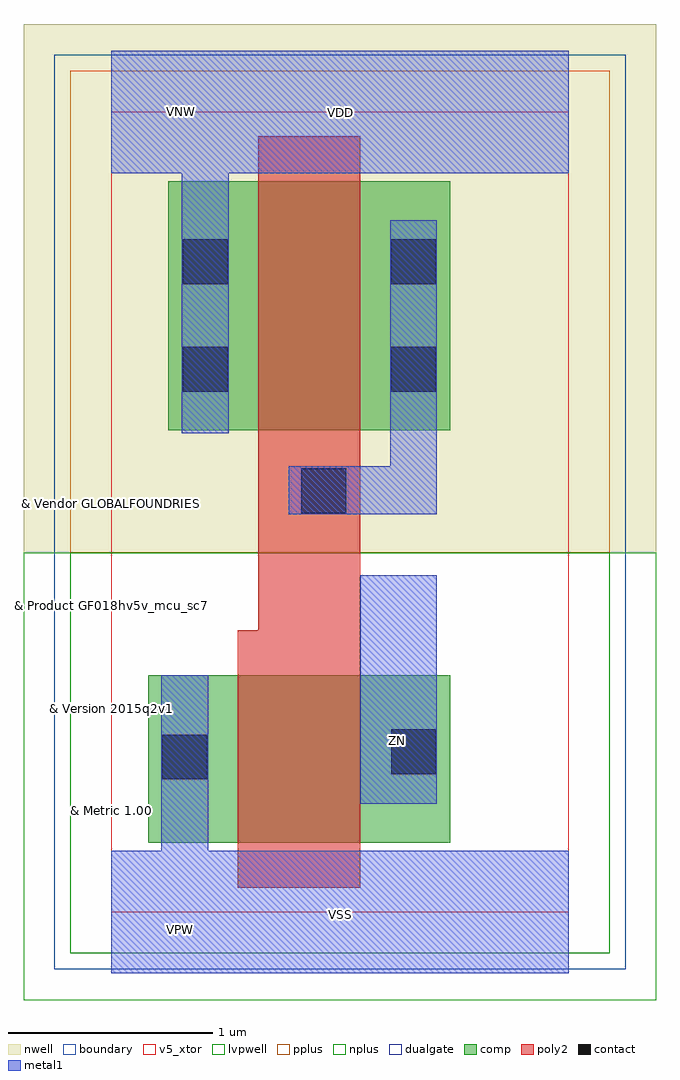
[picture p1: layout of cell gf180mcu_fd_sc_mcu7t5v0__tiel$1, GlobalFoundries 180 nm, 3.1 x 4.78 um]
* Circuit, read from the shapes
.subckt gf180mcu_fd_sc_mcu7t5v0__tiel$1 VDD VNW VSS ZN
XM1 ZN n1 VSS VSUBS nfet_05v0 w=0.82u l=0.6u
XM2 n1 n1 VDD VNW pfet_05v0 w=1.22u l=0.5u
.ends

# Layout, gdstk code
import gdstk
lib = gdstk.Library(unit=1e-6, precision=1e-09)
def R(c, l, rs):  # rectangles x0, y0, x1, y1
    for r in rs: c.add(gdstk.rectangle(r[:2], r[2:], *l))
def P(c, l, *ps):  # polygons
    for p in ps: c.add(gdstk.Polygon(p, *l))
boundary = (0, 0)
nwell = (21, 0)
comp = (22, 0)
poly2 = (30, 0)
pplus = (31, 0)
nplus = (32, 0)
contact = (33, 0)
metal1 = (34, 0)
dualgate = (55, 0)
v5_xtor = (112, 1)
lvpwell = (204, 0)

gf180mcu_fd_sc_mcu7t5v0_ = lib.new_cell('gf180mcu_fd_sc_mcu7t5v0__tiel$1')
R(gf180mcu_fd_sc_mcu7t5v0_, boundary, [(0,0,2.24,3.92)])
R(gf180mcu_fd_sc_mcu7t5v0_, nwell, [(-0.43,1.76,2.67,4.35)])
R(gf180mcu_fd_sc_mcu7t5v0_, comp, [(0.18,0.34,1.66,1.16), (0.28,2.36,1.66,3.58)])
P(gf180mcu_fd_sc_mcu7t5v0_, poly2, [(0.62,0.12),(0.62,1.38),(0.72,1.38),(0.72,3.8),(1.22,3.8),(1.22,0.12)])
R(gf180mcu_fd_sc_mcu7t5v0_, pplus, [(-0.2,1.76,2.44,4.12)])
R(gf180mcu_fd_sc_mcu7t5v0_, nplus, [(-0.2,-0.2,2.44,1.76)])
R(gf180mcu_fd_sc_mcu7t5v0_, contact, [(0.25,0.65,0.47,0.87), (1.37,0.675,1.59,0.895), (0.93,1.955,1.15,2.175), (0.35,2.55,0.57,2.77), (1.37,2.55,1.59,2.77), (0.35,3.075,0.57,3.295), (1.37,3.075,1.59,3.295)])
R(gf180mcu_fd_sc_mcu7t5v0_, metal1, [(1.22,0.53,1.595,1.65)])
P(gf180mcu_fd_sc_mcu7t5v0_, metal1, [(0.87,1.95),(0.87,2.185),(1.365,2.185),(1.365,3.39),(1.595,3.39),(1.595,1.95)],
  [(0,-0.3),(0,0.3),(0.245,0.3),(0.245,1.16),(0.475,1.16),(0.475,0.3),(2.24,0.3),(2.24,-0.3)],
  [(0.345,2.345),(0.345,3.62),(0,3.62),(0,4.22),(2.24,4.22),(2.24,3.62),(0.575,3.62),(0.575,2.345)])
R(gf180mcu_fd_sc_mcu7t5v0_, dualgate, [(-0.28,-0.28,2.52,4.2)])
R(gf180mcu_fd_sc_mcu7t5v0_, v5_xtor, [(0,0,2.24,3.92)])
R(gf180mcu_fd_sc_mcu7t5v0_, lvpwell, [(-0.43,-0.43,2.67,1.76)])
gf180mcu_fd_sc_mcu7t5v0_.add(gdstk.Label('ZN', (1.4,0.84), layer=34, texttype=10))
gf180mcu_fd_sc_mcu7t5v0_.add(gdstk.Label('VDD', (1.12,3.915), layer=34, texttype=10))
gf180mcu_fd_sc_mcu7t5v0_.add(gdstk.Label('VSS', (1.12,-0.01), layer=34, texttype=10))
gf180mcu_fd_sc_mcu7t5v0_.add(gdstk.Label('& Vendor GLOBALFOUNDRIES', (0,2), layer=63, texttype=63))
gf180mcu_fd_sc_mcu7t5v0_.add(gdstk.Label('& Product GF018hv5v_mcu_sc7', (0,1.5), layer=63, texttype=63))
gf180mcu_fd_sc_mcu7t5v0_.add(gdstk.Label('& Version 2015q2v1', (0,1), layer=63, texttype=63))
gf180mcu_fd_sc_mcu7t5v0_.add(gdstk.Label('& Metric 1.00', (0,0.5), layer=63, texttype=63))
gf180mcu_fd_sc_mcu7t5v0_.add(gdstk.Label('VNW', (0.345,3.92), layer=21, texttype=10))
gf180mcu_fd_sc_mcu7t5v0_.add(gdstk.Label('VPW', (0.34,-0.085), layer=204, texttype=10))

lib.write_gds('gf180mcu_fd_sc_mcu7t5v0__tiel_1.gds')
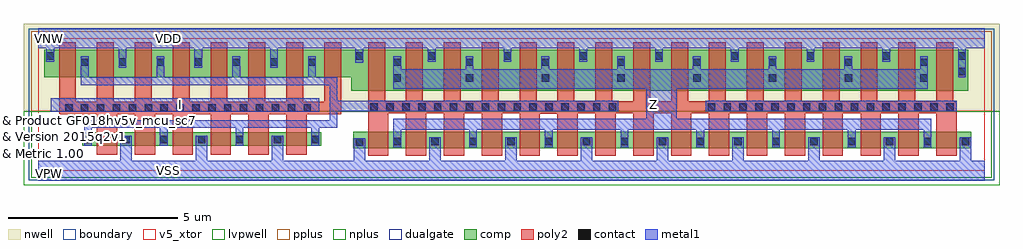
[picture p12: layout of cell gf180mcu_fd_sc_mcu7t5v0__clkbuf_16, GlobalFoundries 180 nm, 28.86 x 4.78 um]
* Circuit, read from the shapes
.subckt gf180mcu_fd_sc_mcu7t5v0__clkbuf_16 I VDD VNW VSS Z
XM1 VSS I n1 VSUBS nfet_05v0 w=0.405u l=0.6u m=6
XM2 Z n1 VSS VSUBS nfet_05v0 w=0.485u l=0.6u m=16
XM3 n1 I VDD VNW pfet_05v0 w=0.82u l=0.5u m=8
XM4 Z n1 VDD VNW pfet_05v0 w=1.22u l=0.5u m=16
.ends

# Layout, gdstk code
import gdstk
lib = gdstk.Library(unit=1e-6, precision=1e-09)
def R(c, l, rs):  # rectangles x0, y0, x1, y1
    for r in rs: c.add(gdstk.rectangle(r[:2], r[2:], *l))
def A(c, l, x, y, w, h, nx, ny, dx, dy):  # array of equal rectangles
    R(c, l, [(x+i*dx, y+j*dy, x+i*dx+w, y+j*dy+h) for i in range(nx) for j in range(ny)])
def P(c, l, *ps):  # polygons
    for p in ps: c.add(gdstk.Polygon(p, *l))
boundary = (0, 0)
nwell = (21, 0)
comp = (22, 0)
poly2 = (30, 0)
pplus = (31, 0)
nplus = (32, 0)
contact = (33, 0)
metal1 = (34, 0)
dualgate = (55, 0)
v5_xtor = (112, 1)
lvpwell = (204, 0)

gf180mcu_fd_sc_mcu7t5v0_ = lib.new_cell('gf180mcu_fd_sc_mcu7t5v0__clkbuf_16')
R(gf180mcu_fd_sc_mcu7t5v0_, boundary, [(0,0,28,3.92)])
R(gf180mcu_fd_sc_mcu7t5v0_, nwell, [(-0.43,1.76,28.43,4.35)])
R(gf180mcu_fd_sc_mcu7t5v0_, comp, [(9.32,0.665,27.6,1.15), (1.3,0.74,8.38,1.145)])
P(gf180mcu_fd_sc_mcu7t5v0_, comp, [(9.26,2.36),(9.26,2.76),(0.18,2.76),(0.18,3.58),(27.5,3.58),(27.5,2.36)])
P(gf180mcu_fd_sc_mcu7t5v0_, poly2, [(1.74,0.47),(1.74,1.675),(0.62,1.675),(0.62,3.8),(1.12,3.8),(1.12,2.035),(1.74,2.035),(1.74,3.8),(2.24,3.8),(2.24,2.035),(2.86,2.035),(2.86,3.8),(3.36,3.8),(3.36,2.035),(3.98,2.035),(3.98,3.8),(4.48,3.8),(4.48,2.035),(5.1,2.035),(5.1,3.8),(5.6,3.8),(5.6,2.035),(6.22,2.035),(6.22,3.8),(6.72,3.8),(6.72,2.035),(7.34,2.035),(7.34,3.8),(7.84,3.8),(7.84,2.035),(8.46,2.035),(8.46,3.8),(8.96,3.8),(8.96,1.675),(7.94,1.675),(7.94,0.47),(7.34,0.47),(7.34,1.675),(6.82,1.675),(6.82,0.47),(6.22,0.47),(6.22,1.675),(5.7,1.675),(5.7,0.47),(5.1,0.47),(5.1,1.675),(4.58,1.675),(4.58,0.47),(3.98,0.47),(3.98,1.675),(3.46,1.675),(3.46,0.47),(2.86,0.47),(2.86,1.675),(2.34,1.675),(2.34,0.47)],
  [(9.76,0.445),(9.76,3.8),(10.26,3.8),(10.26,2.06),(10.88,2.06),(10.88,3.8),(11.38,3.8),(11.38,2.06),(12,2.06),(12,3.8),(12.5,3.8),(12.5,2.06),(13.12,2.06),(13.12,3.8),(13.62,3.8),(13.62,2.06),(14.24,2.06),(14.24,3.8),(14.74,3.8),(14.74,2.06),(15.36,2.06),(15.36,3.8),(15.86,3.8),(15.86,2.06),(16.48,2.06),(16.48,3.8),(16.98,3.8),(16.98,2.06),(17.6,2.06),(17.6,3.8),(18.1,3.8),(18.1,2.06),(18.72,2.06),(18.72,3.8),(19.22,3.8),(19.22,2.06),(19.84,2.06),(19.84,3.8),(20.34,3.8),(20.34,2.06),(20.96,2.06),(20.96,3.8),(21.46,3.8),(21.46,2.06),(22.08,2.06),(22.08,3.8),(22.58,3.8),(22.58,2.06),(23.2,2.06),(23.2,3.8),(23.7,3.8),(23.7,2.06),(24.32,2.06),(24.32,3.8),(24.82,3.8),(24.82,2.06),(25.44,2.06),(25.44,3.8),(25.94,3.8),(25.94,2.06),(26.56,2.06),(26.56,3.8),(27.06,3.8),(27.06,2.06),(27.16,2.06),(27.16,0.445),(26.56,0.445),(26.56,1.7),(26.04,1.7),(26.04,0.445),(25.44,0.445),(25.44,1.7),(24.92,1.7),(24.92,0.445),(24.32,0.445),(24.32,1.7),(23.8,1.7),(23.8,0.445),(23.2,0.445),(23.2,1.7),(22.68,1.7),(22.68,0.445),(22.08,0.445),(22.08,1.7),(21.56,1.7),(21.56,0.445),(20.96,0.445),(20.96,1.7),(20.44,1.7),(20.44,0.445),(19.84,0.445),(19.84,1.7),(19.32,1.7),(19.32,0.445),(18.72,0.445),(18.72,1.7),(18.2,1.7),(18.2,0.445),(17.6,0.445),(17.6,1.7),(17.08,1.7),(17.08,0.445),(16.48,0.445),(16.48,1.7),(15.96,1.7),(15.96,0.445),(15.36,0.445),(15.36,1.69),(14.84,1.69),(14.84,0.445),(14.24,0.445),(14.24,1.7),(13.72,1.7),(13.72,0.445),(13.12,0.445),(13.12,1.7),(12.6,1.7),(12.6,0.445),(12,0.445),(12,1.7),(11.48,1.7),(11.48,0.445),(10.88,0.445),(10.88,1.7),(10.36,1.7),(10.36,0.445)])
R(gf180mcu_fd_sc_mcu7t5v0_, pplus, [(-0.2,1.76,28.2,4.12)])
R(gf180mcu_fd_sc_mcu7t5v0_, nplus, [(-0.2,-0.2,28.2,1.76)])
A(gf180mcu_fd_sc_mcu7t5v0_, contact, 10.51, 0.76, 0.22, 0.22, 16, 1, 1.12, 0)
A(gf180mcu_fd_sc_mcu7t5v0_, contact, 1.37, 0.81, 0.22, 0.22, 7, 1, 1.12, 0)
A(gf180mcu_fd_sc_mcu7t5v0_, contact, 0.8, 1.745, 0.22, 0.22, 16, 1, 0.47, 0)
A(gf180mcu_fd_sc_mcu7t5v0_, contact, 9.83, 1.77, 0.22, 0.22, 16, 1, 0.47, 0)
A(gf180mcu_fd_sc_mcu7t5v0_, contact, 19.8, 1.77, 0.22, 0.22, 16, 1, 0.47, 0)
A(gf180mcu_fd_sc_mcu7t5v0_, contact, 12.65, 2.63, 0.22, 0.22, 7, 2, 2.24, 0.47)
A(gf180mcu_fd_sc_mcu7t5v0_, contact, 1.27, 3.1, 0.22, 0.22, 4, 1, 2.24, 0)
A(gf180mcu_fd_sc_mcu7t5v0_, contact, 2.39, 3.11, 0.22, 0.22, 3, 1, 2.24, 0)
A(gf180mcu_fd_sc_mcu7t5v0_, contact, 11.53, 3.29, 0.22, 0.22, 8, 1, 2.24, 0)
R(gf180mcu_fd_sc_mcu7t5v0_, contact, [(9.39,0.735,9.61,0.955), (10.51,2.63,10.73,2.85), (27.21,2.82,27.43,3.04), (10.51,3.1,10.73,3.32), (0.25,3.29,0.47,3.51), (9.39,3.29,9.61,3.51)])
R(gf180mcu_fd_sc_mcu7t5v0_, metal1, [(0.37,1.74,8.31,2.15), (19.74,1.765,27.16,2.065)])
P(gf180mcu_fd_sc_mcu7t5v0_, metal1, [(1.365,0.74),(1.365,1.5),(8.62,1.5),(8.62,2.53),(1.265,2.53),(1.265,3.39),(1.495,3.39),(1.495,2.76),(3.505,2.76),(3.505,3.39),(3.735,3.39),(3.735,2.76),(5.745,2.76),(5.745,3.39),(5.975,3.39),(5.975,2.76),(7.985,2.76),(7.985,3.39),(8.215,3.39),(8.215,2.76),(8.85,2.76),(8.85,2.065),(17.16,2.065),(17.16,1.765),(8.85,1.765),(8.85,1.27),(8.315,1.27),(8.315,0.74),(8.085,0.74),(8.085,1.27),(6.075,1.27),(6.075,0.74),(5.845,0.74),(5.845,1.27),(3.835,1.27),(3.835,0.74),(3.605,0.74),(3.605,1.27),(1.595,1.27),(1.595,0.74)],
  [(10.505,0.69),(10.505,1.535),(17.985,1.535),(17.985,2.42),(10.505,2.42),(10.505,3.39),(10.735,3.39),(10.735,3),(12.645,3),(12.645,3.39),(12.875,3.39),(12.875,3),(14.885,3),(14.885,3.39),(15.115,3.39),(15.115,3),(17.125,3),(17.125,3.39),(17.355,3.39),(17.355,3),(19.365,3),(19.365,3.39),(19.595,3.39),(19.595,3),(21.605,3),(21.605,3.39),(21.835,3.39),(21.835,3),(23.845,3),(23.845,3.39),(24.075,3.39),(24.075,3),(26.085,3),(26.085,3.39),(26.315,3.39),(26.315,2.42),(18.885,2.42),(18.885,1.535),(26.415,1.535),(26.415,0.69),(26.185,0.69),(26.185,1.215),(24.175,1.215),(24.175,0.69),(23.945,0.69),(23.945,1.215),(21.935,1.215),(21.935,0.69),(21.705,0.69),(21.705,1.215),(19.695,1.215),(19.695,0.69),(19.465,0.69),(19.465,1.215),(17.455,1.215),(17.455,0.69),(17.225,0.69),(17.225,1.215),(15.215,1.215),(15.215,0.69),(14.985,0.69),(14.985,1.215),(12.975,1.215),(12.975,0.69),(12.745,0.69),(12.745,1.215),(10.735,1.215),(10.735,0.69)],
  [(0,-0.3),(0,0.3),(2.43,0.3),(2.43,1.04),(2.77,1.04),(2.77,0.3),(4.67,0.3),(4.67,1.04),(5.01,1.04),(5.01,0.3),(6.91,0.3),(6.91,1.04),(7.25,1.04),(7.25,0.3),(9.33,0.3),(9.33,0.96),(9.67,0.96),(9.67,0.3),(11.57,0.3),(11.57,0.985),(11.91,0.985),(11.91,0.3),(13.81,0.3),(13.81,0.985),(14.15,0.985),(14.15,0.3),(16.05,0.3),(16.05,0.985),(16.39,0.985),(16.39,0.3),(18.29,0.3),(18.29,0.985),(18.63,0.985),(18.63,0.3),(20.53,0.3),(20.53,0.985),(20.87,0.985),(20.87,0.3),(22.77,0.3),(22.77,0.985),(23.11,0.985),(23.11,0.3),(25.01,0.3),(25.01,0.985),(25.35,0.985),(25.35,0.3),(27.25,0.3),(27.25,0.985),(27.59,0.985),(27.59,0.3),(28,0.3),(28,-0.3)],
  [(27.205,2.76),(27.205,3.62),(25.195,3.62),(25.195,3.23),(24.965,3.23),(24.965,3.62),(22.955,3.62),(22.955,3.23),(22.725,3.23),(22.725,3.62),(20.715,3.62),(20.715,3.23),(20.485,3.23),(20.485,3.62),(18.475,3.62),(18.475,3.23),(18.245,3.23),(18.245,3.62),(16.235,3.62),(16.235,3.23),(16.005,3.23),(16.005,3.62),(13.995,3.62),(13.995,3.23),(13.765,3.23),(13.765,3.62),(11.755,3.62),(11.755,3.23),(11.525,3.23),(11.525,3.62),(9.615,3.62),(9.615,3.19),(9.385,3.19),(9.385,3.62),(7.095,3.62),(7.095,3.05),(6.865,3.05),(6.865,3.62),(4.855,3.62),(4.855,3.05),(4.625,3.05),(4.625,3.62),(2.615,3.62),(2.615,3.05),(2.385,3.05),(2.385,3.62),(0.475,3.62),(0.475,3.23),(0.245,3.23),(0.245,3.62),(0,3.62),(0,4.22),(28,4.22),(28,3.62),(27.435,3.62),(27.435,2.76)])
R(gf180mcu_fd_sc_mcu7t5v0_, dualgate, [(-0.28,-0.28,28.28,4.2)])
R(gf180mcu_fd_sc_mcu7t5v0_, v5_xtor, [(0,0,28,3.92)])
R(gf180mcu_fd_sc_mcu7t5v0_, lvpwell, [(-0.43,-0.43,28.43,1.76)])
gf180mcu_fd_sc_mcu7t5v0_.add(gdstk.Label('VDD', (3.855,3.92), layer=34, texttype=10))
gf180mcu_fd_sc_mcu7t5v0_.add(gdstk.Label('VSS', (3.855,0), layer=34, texttype=10))
gf180mcu_fd_sc_mcu7t5v0_.add(gdstk.Label('Z', (18.2,1.96), layer=34, texttype=10))
gf180mcu_fd_sc_mcu7t5v0_.add(gdstk.Label('I', (4.2,1.96), layer=34, texttype=10))
gf180mcu_fd_sc_mcu7t5v0_.add(gdstk.Label('& Vendor GLOBALFOUNDRIES', (0,2), layer=63, texttype=63))
gf180mcu_fd_sc_mcu7t5v0_.add(gdstk.Label('& Product GF018hv5v_mcu_sc7', (0,1.5), layer=63, texttype=63))
gf180mcu_fd_sc_mcu7t5v0_.add(gdstk.Label('& Version 2015q2v1', (0,1), layer=63, texttype=63))
gf180mcu_fd_sc_mcu7t5v0_.add(gdstk.Label('& Metric 1.00', (0,0.5), layer=63, texttype=63))
gf180mcu_fd_sc_mcu7t5v0_.add(gdstk.Label('VNW', (0.345,3.92), layer=21, texttype=10))
gf180mcu_fd_sc_mcu7t5v0_.add(gdstk.Label('VPW', (0.34,-0.085), layer=204, texttype=10))

lib.write_gds('gf180mcu_fd_sc_mcu7t5v0__clkbuf_16.gds')
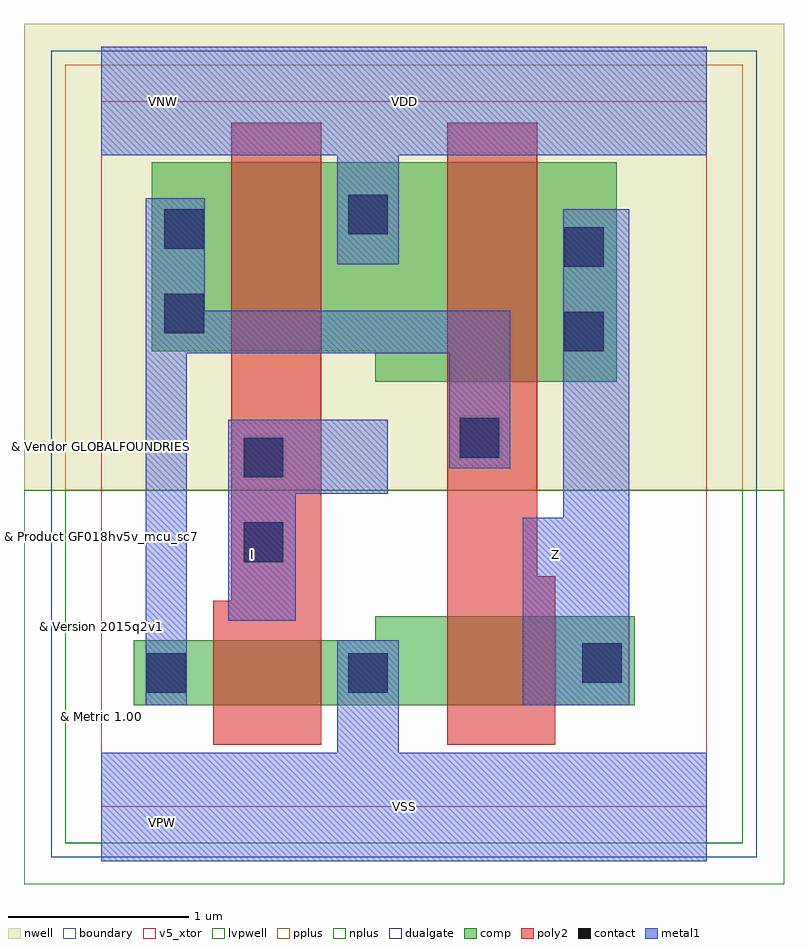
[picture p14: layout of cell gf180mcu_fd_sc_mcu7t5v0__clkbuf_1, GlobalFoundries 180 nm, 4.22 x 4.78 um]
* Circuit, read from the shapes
.subckt gf180mcu_fd_sc_mcu7t5v0__clkbuf_1 I VDD VNW VSS Z
XM1 VSS I n1 VSUBS nfet_05v0 w=0.36u l=0.6u
XM2 Z n1 VSS VSUBS nfet_05v0 w=0.495u l=0.6u
XM3 VDD I n1 VNW pfet_05v0 w=1.05u l=0.5u
XM4 Z n1 VDD VNW pfet_05v0 w=1.22u l=0.5u
.ends

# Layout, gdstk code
import gdstk
lib = gdstk.Library(unit=1e-6, precision=1e-09)
def R(c, l, rs):  # rectangles x0, y0, x1, y1
    for r in rs: c.add(gdstk.rectangle(r[:2], r[2:], *l))
def P(c, l, *ps):  # polygons
    for p in ps: c.add(gdstk.Polygon(p, *l))
boundary = (0, 0)
nwell = (21, 0)
comp = (22, 0)
poly2 = (30, 0)
pplus = (31, 0)
nplus = (32, 0)
contact = (33, 0)
metal1 = (34, 0)
dualgate = (55, 0)
v5_xtor = (112, 1)
lvpwell = (204, 0)

gf180mcu_fd_sc_mcu7t5v0_ = lib.new_cell('gf180mcu_fd_sc_mcu7t5v0__clkbuf_1')
R(gf180mcu_fd_sc_mcu7t5v0_, boundary, [(0,0,3.36,3.92)])
R(gf180mcu_fd_sc_mcu7t5v0_, nwell, [(-0.43,1.76,3.79,4.35)])
P(gf180mcu_fd_sc_mcu7t5v0_, comp, [(1.52,2.36),(1.52,2.53),(0.28,2.53),(0.28,3.58),(2.86,3.58),(2.86,2.36)],
  [(0.18,0.565),(0.18,0.925),(1.52,0.925),(1.52,1.06),(2.96,1.06),(2.96,0.565)])
P(gf180mcu_fd_sc_mcu7t5v0_, poly2, [(0.62,0.345),(0.62,1.145),(0.72,1.145),(0.72,3.8),(1.22,3.8),(1.22,0.345)],
  [(1.92,0.345),(1.92,3.8),(2.42,3.8),(2.42,1.28),(2.52,1.28),(2.52,0.345)])
R(gf180mcu_fd_sc_mcu7t5v0_, pplus, [(-0.2,1.76,3.56,4.12)])
R(gf180mcu_fd_sc_mcu7t5v0_, nplus, [(-0.2,-0.2,3.56,1.76)])
R(gf180mcu_fd_sc_mcu7t5v0_, contact, [(0.25,0.635,0.47,0.855), (1.37,0.635,1.59,0.855), (2.67,0.69,2.89,0.91), (0.79,1.36,1.01,1.58), (0.79,1.83,1.01,2.05), (1.99,1.94,2.21,2.16), (2.57,2.53,2.79,2.75), (0.35,2.63,0.57,2.85), (2.57,3,2.79,3.22), (0.35,3.1,0.57,3.32), (1.37,3.18,1.59,3.4)])
P(gf180mcu_fd_sc_mcu7t5v0_, metal1, [(0.705,1.035),(0.705,2.15),(1.59,2.15),(1.59,1.74),(1.08,1.74),(1.08,1.035)],
  [(0.245,0.565),(0.245,3.38),(0.575,3.38),(0.575,2.755),(2.27,2.755),(2.27,1.88),(1.93,1.88),(1.93,2.52),(0.475,2.52),(0.475,0.565)],
  [(2.34,0.565),(2.34,1.605),(2.565,1.605),(2.565,3.32),(2.93,3.32),(2.93,0.565)],
  [(0,-0.3),(0,0.3),(1.31,0.3),(1.31,0.925),(1.65,0.925),(1.65,0.3),(3.36,0.3),(3.36,-0.3)],
  [(1.31,3.015),(1.31,3.62),(0,3.62),(0,4.22),(3.36,4.22),(3.36,3.62),(1.65,3.62),(1.65,3.015)])
R(gf180mcu_fd_sc_mcu7t5v0_, dualgate, [(-0.28,-0.28,3.64,4.2)])
R(gf180mcu_fd_sc_mcu7t5v0_, v5_xtor, [(0,0,3.36,3.92)])
R(gf180mcu_fd_sc_mcu7t5v0_, lvpwell, [(-0.43,-0.43,3.79,1.76)])
gf180mcu_fd_sc_mcu7t5v0_.add(gdstk.Label('VSS', (1.68,0), layer=34, texttype=10))
gf180mcu_fd_sc_mcu7t5v0_.add(gdstk.Label('Z', (2.52,1.4), layer=34, texttype=10))
gf180mcu_fd_sc_mcu7t5v0_.add(gdstk.Label('I', (0.84,1.4), layer=34, texttype=10))
gf180mcu_fd_sc_mcu7t5v0_.add(gdstk.Label('VDD', (1.68,3.92), layer=34, texttype=10))
gf180mcu_fd_sc_mcu7t5v0_.add(gdstk.Label('& Vendor GLOBALFOUNDRIES', (0,2), layer=63, texttype=63))
gf180mcu_fd_sc_mcu7t5v0_.add(gdstk.Label('& Product GF018hv5v_mcu_sc7', (0,1.5), layer=63, texttype=63))
gf180mcu_fd_sc_mcu7t5v0_.add(gdstk.Label('& Version 2015q2v1', (0,1), layer=63, texttype=63))
gf180mcu_fd_sc_mcu7t5v0_.add(gdstk.Label('& Metric 1.00', (0,0.5), layer=63, texttype=63))
gf180mcu_fd_sc_mcu7t5v0_.add(gdstk.Label('VNW', (0.345,3.92), layer=21, texttype=10))
gf180mcu_fd_sc_mcu7t5v0_.add(gdstk.Label('VPW', (0.34,-0.085), layer=204, texttype=10))

lib.write_gds('gf180mcu_fd_sc_mcu7t5v0__clkbuf_1.gds')
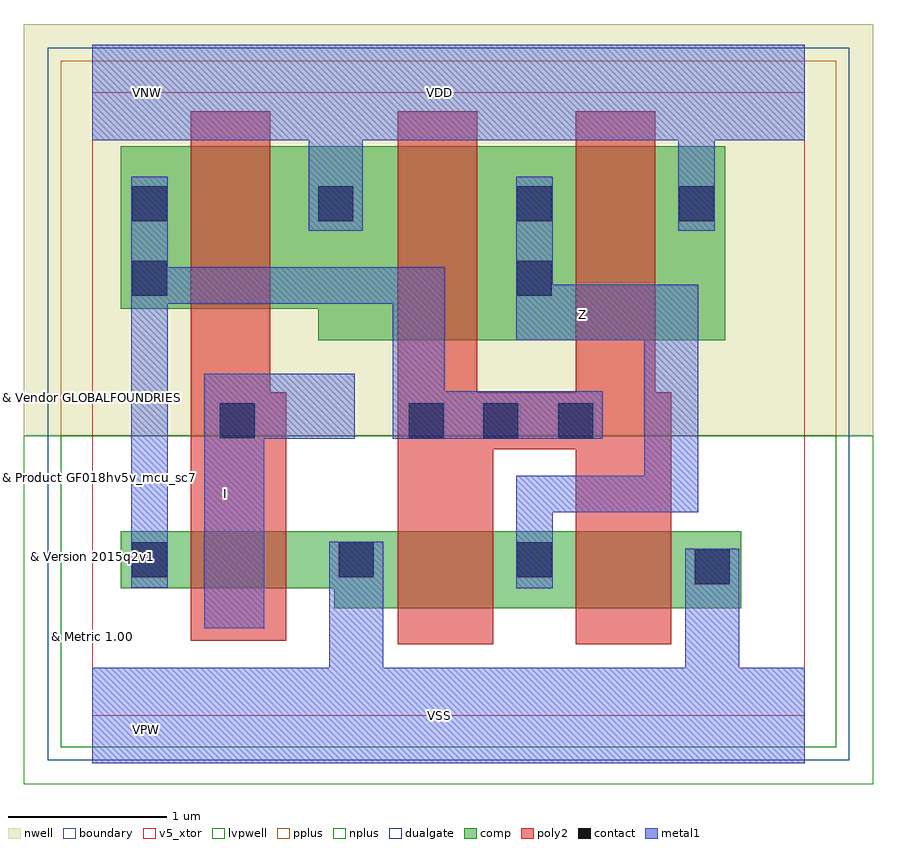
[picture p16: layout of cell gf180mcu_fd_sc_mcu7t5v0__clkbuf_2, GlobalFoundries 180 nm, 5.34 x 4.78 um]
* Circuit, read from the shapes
.subckt gf180mcu_fd_sc_mcu7t5v0__clkbuf_2 I VDD VNW VSS Z
XM1 VSS I n1 VSUBS nfet_05v0 w=0.36u l=0.6u
XM2 Z n1 VSS VSUBS nfet_05v0 w=0.485u l=0.6u m=2
XM3 VDD I n1 VNW pfet_05v0 w=1.02u l=0.5u
XM4 Z n1 VDD VNW pfet_05v0 w=1.22u l=0.5u m=2
.ends

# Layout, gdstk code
import gdstk
lib = gdstk.Library(unit=1e-6, precision=1e-09)
def R(c, l, rs):  # rectangles x0, y0, x1, y1
    for r in rs: c.add(gdstk.rectangle(r[:2], r[2:], *l))
def A(c, l, x, y, w, h, nx, ny, dx, dy):  # array of equal rectangles
    R(c, l, [(x+i*dx, y+j*dy, x+i*dx+w, y+j*dy+h) for i in range(nx) for j in range(ny)])
def P(c, l, *ps):  # polygons
    for p in ps: c.add(gdstk.Polygon(p, *l))
boundary = (0, 0)
nwell = (21, 0)
comp = (22, 0)
poly2 = (30, 0)
pplus = (31, 0)
nplus = (32, 0)
contact = (33, 0)
metal1 = (34, 0)
dualgate = (55, 0)
v5_xtor = (112, 1)
lvpwell = (204, 0)

gf180mcu_fd_sc_mcu7t5v0_ = lib.new_cell('gf180mcu_fd_sc_mcu7t5v0__clkbuf_2')
R(gf180mcu_fd_sc_mcu7t5v0_, boundary, [(0,0,4.48,3.92)])
R(gf180mcu_fd_sc_mcu7t5v0_, nwell, [(-0.43,1.76,4.91,4.35)])
P(gf180mcu_fd_sc_mcu7t5v0_, comp, [(1.42,2.36),(1.42,2.56),(0.18,2.56),(0.18,3.58),(3.98,3.58),(3.98,2.36)],
  [(1.52,0.675),(1.52,0.8),(0.18,0.8),(0.18,1.16),(4.08,1.16),(4.08,0.675)])
P(gf180mcu_fd_sc_mcu7t5v0_, poly2, [(0.62,0.47),(0.62,3.8),(1.12,3.8),(1.12,2.035),(1.22,2.035),(1.22,0.47)],
  [(1.92,0.45),(1.92,3.8),(2.42,3.8),(2.42,2.035),(3.04,2.035),(3.04,3.8),(3.54,3.8),(3.54,2.035),(3.64,2.035),(3.64,0.45),(3.04,0.45),(3.04,1.675),(2.52,1.675),(2.52,0.45)])
R(gf180mcu_fd_sc_mcu7t5v0_, pplus, [(-0.2,1.76,4.68,4.12)])
R(gf180mcu_fd_sc_mcu7t5v0_, nplus, [(-0.2,-0.2,4.68,1.76)])
A(gf180mcu_fd_sc_mcu7t5v0_, contact, 1.99, 1.745, 0.22, 0.22, 3, 1, 0.47, 0)
R(gf180mcu_fd_sc_mcu7t5v0_, contact, [(3.79,0.825,4.01,1.045), (0.25,0.87,0.47,1.09), (1.55,0.87,1.77,1.09), (2.67,0.87,2.89,1.09), (0.8,1.745,1.02,1.965), (0.25,2.64,0.47,2.86), (2.67,2.64,2.89,2.86), (0.25,3.11,0.47,3.33), (1.42,3.11,1.64,3.33), (2.67,3.11,2.89,3.33), (3.69,3.11,3.91,3.33)])
P(gf180mcu_fd_sc_mcu7t5v0_, metal1, [(0.705,0.55),(0.705,2.15),(1.65,2.15),(1.65,1.74),(1.08,1.74),(1.08,0.55)],
  [(0.245,0.805),(0.245,3.39),(0.475,3.39),(0.475,2.82),(2.215,2.82),(2.215,2.04),(3.21,2.04),(3.21,1.74),(1.89,1.74),(1.89,2.59),(0.475,2.59),(0.475,0.805)],
  [(2.665,0.8),(2.665,1.51),(3.47,1.51),(3.47,2.36),(2.665,2.36),(2.665,3.39),(2.895,3.39),(2.895,2.71),(3.81,2.71),(3.81,1.28),(2.895,1.28),(2.895,0.8)],
  [(0,-0.3),(0,0.3),(1.49,0.3),(1.49,1.095),(1.83,1.095),(1.83,0.3),(3.73,0.3),(3.73,1.05),(4.07,1.05),(4.07,0.3),(4.48,0.3),(4.48,-0.3)],
  [(1.36,3.05),(1.36,3.62),(0,3.62),(0,4.22),(4.48,4.22),(4.48,3.62),(3.915,3.62),(3.915,3.05),(3.685,3.05),(3.685,3.62),(1.7,3.62),(1.7,3.05)])
R(gf180mcu_fd_sc_mcu7t5v0_, dualgate, [(-0.28,-0.28,4.76,4.2)])
R(gf180mcu_fd_sc_mcu7t5v0_, v5_xtor, [(0,0,4.48,3.92)])
R(gf180mcu_fd_sc_mcu7t5v0_, lvpwell, [(-0.43,-0.43,4.91,1.76)])
gf180mcu_fd_sc_mcu7t5v0_.add(gdstk.Label('Z', (3.08,2.52), layer=34, texttype=10))
gf180mcu_fd_sc_mcu7t5v0_.add(gdstk.Label('VSS', (2.185,0), layer=34, texttype=10))
gf180mcu_fd_sc_mcu7t5v0_.add(gdstk.Label('VDD', (2.185,3.92), layer=34, texttype=10))
gf180mcu_fd_sc_mcu7t5v0_.add(gdstk.Label('I', (0.84,1.4), layer=34, texttype=10))
gf180mcu_fd_sc_mcu7t5v0_.add(gdstk.Label('& Vendor GLOBALFOUNDRIES', (0,2), layer=63, texttype=63))
gf180mcu_fd_sc_mcu7t5v0_.add(gdstk.Label('& Product GF018hv5v_mcu_sc7', (0,1.5), layer=63, texttype=63))
gf180mcu_fd_sc_mcu7t5v0_.add(gdstk.Label('& Version 2015q2v1', (0,1), layer=63, texttype=63))
gf180mcu_fd_sc_mcu7t5v0_.add(gdstk.Label('& Metric 1.00', (0,0.5), layer=63, texttype=63))
gf180mcu_fd_sc_mcu7t5v0_.add(gdstk.Label('VNW', (0.345,3.92), layer=21, texttype=10))
gf180mcu_fd_sc_mcu7t5v0_.add(gdstk.Label('VPW', (0.34,-0.085), layer=204, texttype=10))

lib.write_gds('gf180mcu_fd_sc_mcu7t5v0__clkbuf_2.gds')
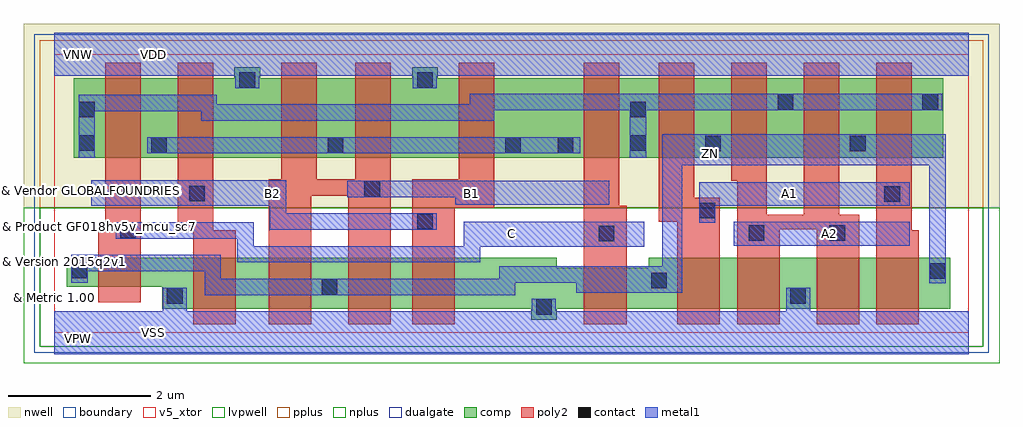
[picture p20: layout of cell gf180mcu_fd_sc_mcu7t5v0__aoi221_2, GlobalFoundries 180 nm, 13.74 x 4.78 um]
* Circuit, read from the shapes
.subckt gf180mcu_fd_sc_mcu7t5v0__aoi221_2 A1 A2 B1 B2 C VDD VNW VSS ZN
XM1 VSS C ZN VSUBS nfet_05v0 w=0.405u l=0.6u
XM2 n1 B2 VSS VSUBS nfet_05v0 w=0.715u l=0.6u
XM3 ZN B1 n1 VSUBS nfet_05v0 w=0.715u l=0.6u
XM4 n2 B1 ZN VSUBS nfet_05v0 w=0.715u l=0.6u
XM5 VSS B2 n2 VSUBS nfet_05v0 w=0.715u l=0.6u
XM6 ZN C VSS VSUBS nfet_05v0 w=0.575u l=0.6u
XM7 n3 A1 ZN VSUBS nfet_05v0 w=0.715u l=0.6u
XM8 VSS A2 n3 VSUBS nfet_05v0 w=0.715u l=0.6u
XM9 n4 A2 VSS VSUBS nfet_05v0 w=0.715u l=0.6u
XM10 ZN A1 n4 VSUBS nfet_05v0 w=0.715u l=0.6u
XM11 n5 C n6 VNW pfet_05v0 w=1.12u l=0.5u m=2
XM12 VDD B2 n5 VNW pfet_05v0 w=1.12u l=0.5u m=2
XM13 n5 B1 VDD VNW pfet_05v0 w=1.12u l=0.5u m=2
XM14 ZN A1 n6 VNW pfet_05v0 w=1.12u l=0.5u m=2
XM15 n6 A2 ZN VNW pfet_05v0 w=1.12u l=0.5u m=2
.ends

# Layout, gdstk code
import gdstk
lib = gdstk.Library(unit=1e-6, precision=1e-09)
def R(c, l, rs):  # rectangles x0, y0, x1, y1
    for r in rs: c.add(gdstk.rectangle(r[:2], r[2:], *l))
def P(c, l, *ps):  # polygons
    for p in ps: c.add(gdstk.Polygon(p, *l))
boundary = (0, 0)
nwell = (21, 0)
comp = (22, 0)
poly2 = (30, 0)
pplus = (31, 0)
nplus = (32, 0)
contact = (33, 0)
metal1 = (34, 0)
dualgate = (55, 0)
v5_xtor = (112, 1)
lvpwell = (204, 0)

gf180mcu_fd_sc_mcu7t5v0_ = lib.new_cell('gf180mcu_fd_sc_mcu7t5v0__aoi221_2')
R(gf180mcu_fd_sc_mcu7t5v0_, boundary, [(0,0,12.88,3.92)])
R(gf180mcu_fd_sc_mcu7t5v0_, nwell, [(-0.43,1.76,13.31,4.35)])
P(gf180mcu_fd_sc_mcu7t5v0_, comp, [(0.28,2.46),(0.28,3.58),(2.54,3.58),(2.54,3.74),(2.9,3.74),(2.9,3.58),(5.04,3.58),(5.04,3.74),(5.4,3.74),(5.4,3.58),(12.515,3.58),(12.515,2.46)],
  [(6.715,0.18),(6.715,0.34),(1.52,0.34),(1.52,0.65),(0.18,0.65),(0.18,1.055),(7.075,1.055),(7.075,0.915),(8.375,0.915),(8.375,1.055),(12.615,1.055),(12.615,0.34),(7.075,0.34),(7.075,0.18)])
P(gf180mcu_fd_sc_mcu7t5v0_, poly2, [(0.62,0.43),(0.62,1.44),(0.72,1.44),(0.72,3.8),(1.22,3.8),(1.22,0.43)],
  [(1.96,0.12),(1.96,1.46),(1.74,1.46),(1.74,3.8),(2.24,3.8),(2.24,1.44),(2.56,1.44),(2.56,0.12)],
  [(3.02,0.12),(3.02,2.16),(3.2,2.16),(3.2,3.8),(3.7,3.8),(3.7,2.16),(4.24,2.16),(4.24,3.8),(4.74,3.8),(4.74,0.12),(4.14,0.12),(4.14,1.93),(3.62,1.93),(3.62,0.12)],
  [(5.04,0.12),(5.04,2.16),(5.7,2.16),(5.7,3.8),(6.2,3.8),(6.2,1.76),(5.64,1.76),(5.64,0.12)],
  [(7.46,0.12),(7.46,3.8),(7.96,3.8),(7.96,1.79),(8.06,1.79),(8.06,0.12)],
  [(8.775,0.12),(8.775,1.56),(8.515,1.56),(8.515,3.8),(9.015,3.8),(9.015,1.9),(9.375,1.9),(9.375,0.12)],
  [(9.615,0.12),(9.615,2.14),(9.535,2.14),(9.535,3.8),(10.035,3.8),(10.035,1.66),(10.555,1.66),(10.555,3.8),(11.055,3.8),(11.055,1.66),(11.335,1.66),(11.335,0.12),(10.735,0.12),(10.735,1.46),(10.215,1.46),(10.215,0.12)],
  [(11.575,0.12),(11.575,3.8),(12.075,3.8),(12.075,1.44),(12.175,1.44),(12.175,0.12)])
R(gf180mcu_fd_sc_mcu7t5v0_, pplus, [(-0.2,1.76,13.08,4.12)])
R(gf180mcu_fd_sc_mcu7t5v0_, nplus, [(-0.2,-0.2,13.08,1.76)])
R(gf180mcu_fd_sc_mcu7t5v0_, contact, [(6.785,0.25,7.005,0.47), (1.59,0.41,1.81,0.63), (10.365,0.41,10.585,0.63), (3.77,0.535,3.99,0.755), (8.405,0.625,8.625,0.845), (12.325,0.76,12.545,0.98), (0.25,0.765,0.47,0.985), (7.665,1.285,7.885,1.505), (9.78,1.295,10,1.515), (10.915,1.295,11.135,1.515), (0.93,1.33,1.15,1.55), (5.11,1.455,5.33,1.675), (9.085,1.61,9.305,1.83), (11.69,1.845,11.91,2.065), (1.9,1.85,2.12,2.07), (4.37,1.915,4.59,2.135), (1.37,2.53,1.59,2.75), (3.85,2.53,4.07,2.75), (6.35,2.53,6.57,2.75), (7.09,2.53,7.31,2.75), (9.165,2.555,9.385,2.775), (11.205,2.555,11.425,2.775), (0.35,2.56,0.57,2.78), (8.11,2.56,8.33,2.78), (0.35,3.03,0.57,3.25), (8.11,3.03,8.33,3.25), (10.185,3.14,10.405,3.36), (12.225,3.14,12.445,3.36), (2.61,3.45,2.83,3.67), (5.11,3.45,5.33,3.67)])
R(gf180mcu_fd_sc_mcu7t5v0_, metal1, [(9.57,1.225,12.05,1.56), (1.31,2.525,7.41,2.755)])
P(gf180mcu_fd_sc_mcu7t5v0_, metal1, [(3.04,1.45),(3.04,1.785),(0.525,1.785),(0.525,2.15),(3.27,2.15),(3.27,1.68),(5.39,1.68),(5.39,1.45)],
  [(5.65,1.8),(5.65,1.91),(4.125,1.91),(4.125,2.14),(7.815,2.14),(7.815,1.8)],
  [(2.58,0.99),(2.58,1.325),(0.87,1.325),(0.87,1.555),(2.81,1.555),(2.81,1.22),(5.77,1.22),(5.77,1.56),(8.31,1.56),(8.31,1.21),(6,1.21),(6,0.99)],
  [(9.08,1.55),(9.08,2.12),(12.05,2.12),(12.05,1.79),(9.31,1.79),(9.31,1.55)],
  [(0.345,2.46),(0.345,3.35),(2.29,3.35),(2.29,3.215),(5.855,3.215),(5.855,3.365),(12.505,3.365),(12.505,3.135),(8.335,3.135),(8.335,2.46),(8.105,2.46),(8.105,3.135),(6.195,3.135),(6.195,2.985),(2.075,2.985),(2.075,3.12),(0.575,3.12),(0.575,2.46)],
  [(2.12,0.53),(2.12,0.865),(0.475,0.865),(0.475,0.705),(0.245,0.705),(0.245,1.095),(2.35,1.095),(2.35,0.76),(6.265,0.76),(6.265,0.935),(8.565,0.935),(8.565,2.795),(12.55,2.795),(12.55,0.7),(12.32,0.7),(12.32,2.36),(8.845,2.36),(8.845,0.565),(7.35,0.565),(7.35,0.705),(6.495,0.705),(6.495,0.53)],
  [(0,-0.3),(0,0.3),(1.53,0.3),(1.53,0.635),(1.87,0.635),(1.87,0.3),(6.725,0.3),(6.725,0.475),(7.065,0.475),(7.065,0.3),(10.305,0.3),(10.305,0.635),(10.645,0.635),(10.645,0.3),(12.88,0.3),(12.88,-0.3)],
  [(2.55,3.445),(2.55,3.62),(0,3.62),(0,4.22),(12.88,4.22),(12.88,3.62),(5.39,3.62),(5.39,3.445),(5.05,3.445),(5.05,3.62),(2.89,3.62),(2.89,3.445)])
R(gf180mcu_fd_sc_mcu7t5v0_, dualgate, [(-0.28,-0.28,13.16,4.2)])
R(gf180mcu_fd_sc_mcu7t5v0_, v5_xtor, [(0,0,12.88,3.92)])
R(gf180mcu_fd_sc_mcu7t5v0_, lvpwell, [(-0.43,-0.43,13.31,1.76)])
gf180mcu_fd_sc_mcu7t5v0_.add(gdstk.Label('B1', (5.88,1.96), layer=34, texttype=10))
gf180mcu_fd_sc_mcu7t5v0_.add(gdstk.Label('B2', (3.08,1.96), layer=34, texttype=10))
gf180mcu_fd_sc_mcu7t5v0_.add(gdstk.Label('VDD', (1.4,3.92), layer=34, texttype=10))
gf180mcu_fd_sc_mcu7t5v0_.add(gdstk.Label('VSS', (1.4,0), layer=34, texttype=10))
gf180mcu_fd_sc_mcu7t5v0_.add(gdstk.Label('ZN', (9.24,2.52), layer=34, texttype=10))
gf180mcu_fd_sc_mcu7t5v0_.add(gdstk.Label('A1', (10.36,1.96), layer=34, texttype=10))
gf180mcu_fd_sc_mcu7t5v0_.add(gdstk.Label('A2', (10.92,1.4), layer=34, texttype=10))
gf180mcu_fd_sc_mcu7t5v0_.add(gdstk.Label('C', (6.44,1.4), layer=34, texttype=10))
gf180mcu_fd_sc_mcu7t5v0_.add(gdstk.Label('& Vendor GLOBALFOUNDRIES', (0,2), layer=63, texttype=63))
gf180mcu_fd_sc_mcu7t5v0_.add(gdstk.Label('& Product GF018hv5v_mcu_sc7', (0,1.5), layer=63, texttype=63))
gf180mcu_fd_sc_mcu7t5v0_.add(gdstk.Label('& Version 2015q2v1', (0,1), layer=63, texttype=63))
gf180mcu_fd_sc_mcu7t5v0_.add(gdstk.Label('& Metric 1.00', (0,0.5), layer=63, texttype=63))
gf180mcu_fd_sc_mcu7t5v0_.add(gdstk.Label('VNW', (0.345,3.92), layer=21, texttype=10))
gf180mcu_fd_sc_mcu7t5v0_.add(gdstk.Label('VPW', (0.34,-0.085), layer=204, texttype=10))

lib.write_gds('gf180mcu_fd_sc_mcu7t5v0__aoi221_2.gds')
